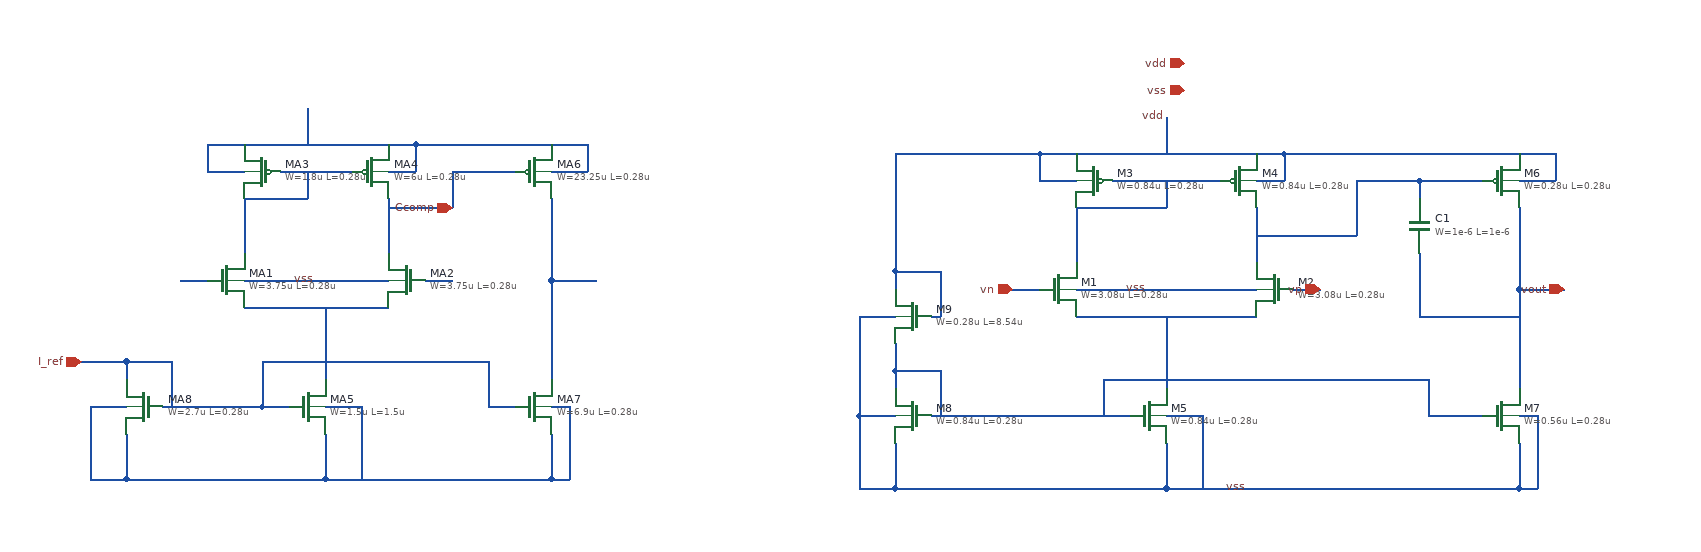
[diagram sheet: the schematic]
v {xschem version=3.4.7 file_version=1.2}
G {}
K {}
V {}
S {}
E {}
N 150 -160 310 -160 {lab=#net1}
N 220 -200 220 -160 {lab=#net1}
N 110 -130 150 -130 {lab=#net1}
N 110 -160 110 -130 {lab=#net1}
N 110 -160 150 -160 {lab=#net1}
N 310 -130 340 -130 {lab=#net1}
N 340 -160 340 -130 {lab=#net1}
N 310 -160 340 -160 {lab=#net1}
N 190 -130 270 -130 {lab=#net2}
N 150 -100 220 -100 {lab=#net2}
N 220 -130 220 -100 {lab=#net2}
N 340 -160 490 -160 {lab=#net1}
N 490 -130 530 -130 {lab=#net1}
N 530 -160 530 -130 {lab=#net1}
N 490 -160 530 -160 {lab=#net1}
N 80 -10 110 -10 {lab=#net3}
N 230 -10 310 -10 {lab=vss}
N 150 -10 230 -10 {lab=vss}
N 150 -100 150 -40 {lab=#net2}
N 310 -100 310 -40 {lab=Ccomp}
N 150 20 310 20 {lab=#net4}
N 350 -10 380 -10 {lab=#net5}
N 380 -130 450 -130 {lab=Ccomp}
N 380 -130 380 -90 {lab=Ccomp}
N 310 -90 380 -90 {lab=Ccomp}
N 490 -100 490 -10 {lab=#net6}
N 490 -10 540 -10 {lab=#net6}
N 490 -10 490 100 {lab=#net6}
N 490 160 490 210 {lab=#net7}
N 310 210 490 210 {lab=#net7}
N 490 130 510 130 {lab=#net7}
N 510 130 510 210 {lab=#net7}
N 490 210 510 210 {lab=#net7}
N 240 20 240 100 {lab=#net4}
N 240 160 240 210 {lab=#net7}
N 240 210 310 210 {lab=#net7}
N 240 130 280 130 {lab=#net7}
N 280 130 280 210 {lab=#net7}
N 420 130 450 130 {lab=I_ref}
N 420 80 420 130 {lab=I_ref}
N 170 80 420 80 {lab=I_ref}
N 170 80 170 130 {lab=I_ref}
N 170 130 200 130 {lab=I_ref}
N 60 130 170 130 {lab=I_ref}
N 20 160 20 210 {lab=#net7}
N 20 210 240 210 {lab=#net7}
N -20 130 20 130 {lab=#net7}
N -20 130 -20 210 {lab=#net7}
N -20 210 20 210 {lab=#net7}
N 20 80 20 100 {lab=I_ref}
N 20 80 70 80 {lab=I_ref}
N 70 80 70 130 {lab=I_ref}
N -30 80 20 80 {lab=I_ref}
N 1070 -150 1230 -150 {lab=vdd}
N 1170 -190 1170 -150 {lab=vdd}
N 1030 -120 1070 -120 {lab=vdd}
N 1030 -150 1030 -120 {lab=vdd}
N 1030 -150 1070 -150 {lab=vdd}
N 1270 -120 1300 -120 {lab=vdd}
N 1300 -150 1300 -120 {lab=vdd}
N 1270 -150 1300 -150 {lab=vdd}
N 1110 -120 1190 -120 {lab=#net8}
N 1100 -90 1170 -90 {lab=#net8}
N 1170 -120 1170 -90 {lab=#net8}
N 1000 0 1030 0 {lab=vn}
N 1150 0 1230 0 {lab=vss}
N 1070 0 1150 0 {lab=vss}
N 1070 -90 1070 -30 {lab=#net8}
N 1270 -90 1270 -30 {lab=#net9}
N 1070 30 1230 30 {lab=#net10}
N 1310 0 1340 0 {lab=vp}
N 1170 30 1170 110 {lab=#net10}
N 1170 170 1170 220 {lab=vss}
N 1170 220 1240 220 {lab=vss}
N 1170 140 1210 140 {lab=vss}
N 1210 140 1210 220 {lab=vss}
N 870 170 870 220 {lab=vss}
N 830 140 870 140 {lab=vss}
N 830 140 830 220 {lab=vss}
N 830 220 870 220 {lab=vss}
N 870 90 870 110 {lab=#net11}
N 870 90 920 90 {lab=#net11}
N 920 90 920 140 {lab=#net11}
N 910 30 920 30 {lab=vdd}
N 920 -20 920 30 {lab=vdd}
N 870 -20 920 -20 {lab=vdd}
N 870 -20 870 0 {lab=vdd}
N 870 -150 870 -20 {lab=vdd}
N 870 -150 1030 -150 {lab=vdd}
N 830 30 870 30 {lab=vss}
N 830 30 830 140 {lab=vss}
N 870 60 870 90 {lab=#net11}
N 1230 30 1270 30 {lab=#net10}
N 1230 0 1270 0 {lab=vss}
N 1190 -120 1230 -120 {lab=#net8}
N 1230 -150 1270 -150 {lab=vdd}
N 1070 -90 1100 -90 {lab=#net8}
N 910 140 1130 140 {lab=#net11}
N 870 220 1170 220 {lab=vss}
N 1560 -120 1600 -120 {lab=vdd}
N 1600 -150 1600 -120 {lab=vdd}
N 1560 -150 1600 -150 {lab=vdd}
N 1560 -90 1560 0 {lab=vout}
N 1560 0 1610 0 {lab=vout}
N 1560 0 1560 110 {lab=vout}
N 1560 170 1560 220 {lab=vss}
N 1560 140 1580 140 {lab=vss}
N 1580 140 1580 220 {lab=vss}
N 1560 220 1580 220 {lab=vss}
N 1300 -150 1560 -150 {lab=vdd}
N 1450 -120 1520 -120 {lab=#net9}
N 1450 -120 1450 -100 {lab=#net9}
N 1380 -120 1450 -120 {lab=#net9}
N 1380 -120 1380 -60 {lab=#net9}
N 1270 -60 1380 -60 {lab=#net9}
N 1450 -40 1450 30 {lab=vout}
N 1100 100 1100 140 {lab=#net11}
N 1100 100 1460 100 {lab=#net11}
N 1460 100 1460 140 {lab=#net11}
N 1460 140 1520 140 {lab=#net11}
N 1240 220 1560 220 {lab=vss}
N 1450 30 1560 30 {lab=vout}
C {symbols/pfet_03v3.sym} 170 -130 0 1 {name=MA3
L=0.28u
W=1.8u
nf=1
m=6
ad="'int((nf+1)/2) * W/nf * 0.18u'"
pd="'2*int((nf+1)/2) * (W/nf + 0.18u)'"
as="'int((nf+2)/2) * W/nf * 0.18u'"
ps="'2*int((nf+2)/2) * (W/nf + 0.18u)'"
nrd="'0.18u / W'" nrs="'0.18u / W'"
sa=0 sb=0 sd=0
model=pfet_03v3
spiceprefix=X
}
C {symbols/nfet_03v3.sym} 130 -10 0 0 {name=MA1
L=0.28u
W=3.75u
nf=1
m=1
ad="'int((nf+1)/2) * W/nf * 0.18u'"
pd="'2*int((nf+1)/2) * (W/nf + 0.18u)'"
as="'int((nf+2)/2) * W/nf * 0.18u'"
ps="'2*int((nf+2)/2) * (W/nf + 0.18u)'"
nrd="'0.18u / W'" nrs="'0.18u / W'"
sa=0 sb=0 sd=0
model=nfet_03v3
spiceprefix=X
}
C {symbols/pfet_03v3.sym} 290 -130 0 0 {name=MA4
L=0.28u
W=6u
nf=1
m=6
ad="'int((nf+1)/2) * W/nf * 0.18u'"
pd="'2*int((nf+1)/2) * (W/nf + 0.18u)'"
as="'int((nf+2)/2) * W/nf * 0.18u'"
ps="'2*int((nf+2)/2) * (W/nf + 0.18u)'"
nrd="'0.18u / W'" nrs="'0.18u / W'"
sa=0 sb=0 sd=0
model=pfet_03v3
spiceprefix=X
}
C {symbols/pfet_03v3.sym} 470 -130 0 0 {name=MA6
L=0.28u
W=23.25u
nf=1
m=6
ad="'int((nf+1)/2) * W/nf * 0.18u'"
pd="'2*int((nf+1)/2) * (W/nf + 0.18u)'"
as="'int((nf+2)/2) * W/nf * 0.18u'"
ps="'2*int((nf+2)/2) * (W/nf + 0.18u)'"
nrd="'0.18u / W'" nrs="'0.18u / W'"
sa=0 sb=0 sd=0
model=pfet_03v3
spiceprefix=X
}
C {symbols/nfet_03v3.sym} 330 -10 0 1 {name=MA2
L=0.28u
W=3.75u
nf=1
m=1
ad="'int((nf+1)/2) * W/nf * 0.18u'"
pd="'2*int((nf+1)/2) * (W/nf + 0.18u)'"
as="'int((nf+2)/2) * W/nf * 0.18u'"
ps="'2*int((nf+2)/2) * (W/nf + 0.18u)'"
nrd="'0.18u / W'" nrs="'0.18u / W'"
sa=0 sb=0 sd=0
model=nfet_03v3
spiceprefix=X
}
C {symbols/nfet_03v3.sym} 220 130 0 0 {name=MA5
L=1.5u
W=1.5u
nf=1
m=1
ad="'int((nf+1)/2) * W/nf * 0.18u'"
pd="'2*int((nf+1)/2) * (W/nf + 0.18u)'"
as="'int((nf+2)/2) * W/nf * 0.18u'"
ps="'2*int((nf+2)/2) * (W/nf + 0.18u)'"
nrd="'0.18u / W'" nrs="'0.18u / W'"
sa=0 sb=0 sd=0
model=nfet_03v3
spiceprefix=X
}
C {symbols/nfet_03v3.sym} 470 130 0 0 {name=MA7
L=0.28u
W=6.9u
nf=1
m=1
ad="'int((nf+1)/2) * W/nf * 0.18u'"
pd="'2*int((nf+1)/2) * (W/nf + 0.18u)'"
as="'int((nf+2)/2) * W/nf * 0.18u'"
ps="'2*int((nf+2)/2) * (W/nf + 0.18u)'"
nrd="'0.18u / W'" nrs="'0.18u / W'"
sa=0 sb=0 sd=0
model=nfet_03v3
spiceprefix=X
}
C {symbols/nfet_03v3.sym} 40 130 0 1 {name=MA8
L=0.28u
W=2.7u
nf=1
m=1
ad="'int((nf+1)/2) * W/nf * 0.18u'"
pd="'2*int((nf+1)/2) * (W/nf + 0.18u)'"
as="'int((nf+2)/2) * W/nf * 0.18u'"
ps="'2*int((nf+2)/2) * (W/nf + 0.18u)'"
nrd="'0.18u / W'" nrs="'0.18u / W'"
sa=0 sb=0 sd=0
model=nfet_03v3
spiceprefix=X
}
C {lab_pin.sym} 230 -10 1 0 {name=p4 sig_type=std_logic lab=vss}
C {iopin.sym} 380 -90 0 0 {name=p10 lab=Ccomp}
C {iopin.sym} -30 80 2 0 {name=p12 lab=I_ref}
C {title.sym} 150 350 0 0 {name=l1 author="Oscar Islas"}
C {symbols/pfet_03v3.sym} 1090 -120 0 1 {name=M3
L=0.28u
W=0.84u
nf=1
m=1
ad="'int((nf+1)/2) * W/nf * 0.18u'"
pd="'2*int((nf+1)/2) * (W/nf + 0.18u)'"
as="'int((nf+2)/2) * W/nf * 0.18u'"
ps="'2*int((nf+2)/2) * (W/nf + 0.18u)'"
nrd="'0.18u / W'" nrs="'0.18u / W'"
sa=0 sb=0 sd=0
model=pfet_03v3
spiceprefix=X
}
C {symbols/nfet_03v3.sym} 1050 0 0 0 {name=M1
L=0.28u
W=3.08u
nf=1
m=1
ad="'int((nf+1)/2) * W/nf * 0.18u'"
pd="'2*int((nf+1)/2) * (W/nf + 0.18u)'"
as="'int((nf+2)/2) * W/nf * 0.18u'"
ps="'2*int((nf+2)/2) * (W/nf + 0.18u)'"
nrd="'0.18u / W'" nrs="'0.18u / W'"
sa=0 sb=0 sd=0
model=nfet_03v3
spiceprefix=X
}
C {iopin.sym} 1190 -250 0 0 {name=p13 lab=vdd}
C {iopin.sym} 1190 -220 0 0 {name=p14 lab=vss}
C {symbols/pfet_03v3.sym} 1250 -120 0 0 {name=M4
L=0.28u
W=0.84u
nf=1
m=1
ad="'int((nf+1)/2) * W/nf * 0.18u'"
pd="'2*int((nf+1)/2) * (W/nf + 0.18u)'"
as="'int((nf+2)/2) * W/nf * 0.18u'"
ps="'2*int((nf+2)/2) * (W/nf + 0.18u)'"
nrd="'0.18u / W'" nrs="'0.18u / W'"
sa=0 sb=0 sd=0
model=pfet_03v3
spiceprefix=X
}
C {symbols/nfet_03v3.sym} 1290 0 0 1 {name=M2
L=0.28u
W=3.08u
nf=1
m=1
ad="'int((nf+1)/2) * W/nf * 0.18u'"
pd="'2*int((nf+1)/2) * (W/nf + 0.18u)'"
as="'int((nf+2)/2) * W/nf * 0.18u'"
ps="'2*int((nf+2)/2) * (W/nf + 0.18u)'"
nrd="'0.18u / W'" nrs="'0.18u / W'"
sa=0 sb=0 sd=0
model=nfet_03v3
spiceprefix=X
}
C {symbols/nfet_03v3.sym} 1150 140 0 0 {name=M5
L=0.28u
W=0.84u
nf=1
m=1
ad="'int((nf+1)/2) * W/nf * 0.18u'"
pd="'2*int((nf+1)/2) * (W/nf + 0.18u)'"
as="'int((nf+2)/2) * W/nf * 0.18u'"
ps="'2*int((nf+2)/2) * (W/nf + 0.18u)'"
nrd="'0.18u / W'" nrs="'0.18u / W'"
sa=0 sb=0 sd=0
model=nfet_03v3
spiceprefix=X
}
C {symbols/nfet_03v3.sym} 890 140 0 1 {name=M8
L=0.28u
W=0.84u
nf=1
m=1
ad="'int((nf+1)/2) * W/nf * 0.18u'"
pd="'2*int((nf+1)/2) * (W/nf + 0.18u)'"
as="'int((nf+2)/2) * W/nf * 0.18u'"
ps="'2*int((nf+2)/2) * (W/nf + 0.18u)'"
nrd="'0.18u / W'" nrs="'0.18u / W'"
sa=0 sb=0 sd=0
model=nfet_03v3
spiceprefix=X
}
C {lab_pin.sym} 1170 -190 0 0 {name=p16 sig_type=std_logic lab=vdd}
C {iopin.sym} 1000 0 2 0 {name=p17 lab=vn}
C {lab_pin.sym} 1150 0 1 0 {name=p18 sig_type=std_logic lab=vss}
C {iopin.sym} 1340 0 0 0 {name=p19 lab=vp}
C {lab_pin.sym} 1260 220 3 0 {name=p21 sig_type=std_logic lab=vss}
C {symbols/nfet_03v3.sym} 890 30 0 1 {name=M9
L=8.54u
W=0.28u
nf=1
m=1
ad="'int((nf+1)/2) * W/nf * 0.18u'"
pd="'2*int((nf+1)/2) * (W/nf + 0.18u)'"
as="'int((nf+2)/2) * W/nf * 0.18u'"
ps="'2*int((nf+2)/2) * (W/nf + 0.18u)'"
nrd="'0.18u / W'" nrs="'0.18u / W'"
sa=0 sb=0 sd=0
model=nfet_03v3
spiceprefix=X
}
C {symbols/pfet_03v3.sym} 1540 -120 0 0 {name=M6
L=0.28u
W=0.28u
nf=1
m=6
ad="'int((nf+1)/2) * W/nf * 0.18u'"
pd="'2*int((nf+1)/2) * (W/nf + 0.18u)'"
as="'int((nf+2)/2) * W/nf * 0.18u'"
ps="'2*int((nf+2)/2) * (W/nf + 0.18u)'"
nrd="'0.18u / W'" nrs="'0.18u / W'"
sa=0 sb=0 sd=0
model=pfet_03v3
spiceprefix=X
}
C {symbols/nfet_03v3.sym} 1540 140 0 0 {name=M7
L=0.28u
W=0.56u
nf=1
m=1
ad="'int((nf+1)/2) * W/nf * 0.18u'"
pd="'2*int((nf+1)/2) * (W/nf + 0.18u)'"
as="'int((nf+2)/2) * W/nf * 0.18u'"
ps="'2*int((nf+2)/2) * (W/nf + 0.18u)'"
nrd="'0.18u / W'" nrs="'0.18u / W'"
sa=0 sb=0 sd=0
model=nfet_03v3
spiceprefix=X
}
C {iopin.sym} 1610 0 0 0 {name=p15 lab=vout}
C {symbols/cap_mim_2f0fF.sym} 1450 -70 0 0 {name=C1
W=1e-6
L=1e-6
model=cap_mim_2f0fF
spiceprefix=X
m=100}
